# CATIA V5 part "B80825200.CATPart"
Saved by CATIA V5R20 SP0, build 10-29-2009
Part number: B80825200
Revision: 3
Definition: design
Nomenclature: B80825200
Source: made
Description: NOT SPECIFIED
Bounding box of the stored display mesh (mm): x -15 to 15, y -15 to 15, z 0 to 200
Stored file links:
  C:\Users\Raffaele\Desktop\3D X SITO CF\BOLEX\4-PILLAR REF 808\B80825200.CATPart

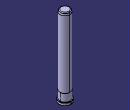
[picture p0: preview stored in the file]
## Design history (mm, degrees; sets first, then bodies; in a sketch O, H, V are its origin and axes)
Body1 "MANIFOLD_SOLID_BREP #450" (main body)
  Solid1: solid without history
